VERSION 5.7 ;
  NOWIREEXTENSIONATPIN ON ;
  DIVIDERCHAR "/" ;
  BUSBITCHARS "[]" ;
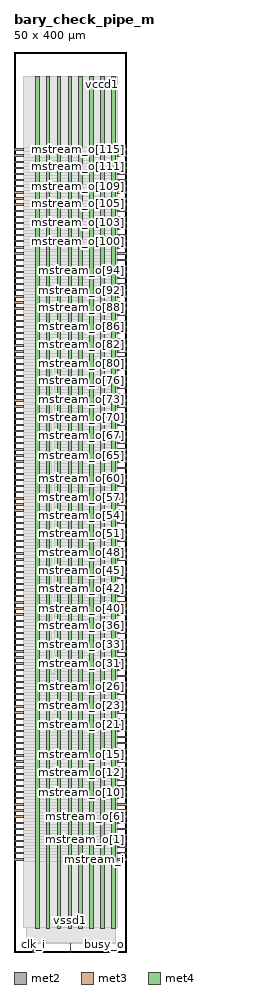
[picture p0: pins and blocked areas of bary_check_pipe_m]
MACRO bary_check_pipe_m
  CLASS BLOCK ;
  FOREIGN bary_check_pipe_m ;
  ORIGIN 0.000 0.000 ;
  SIZE 50.000 BY 400.000 ;
  PIN busy_o
    DIRECTION OUTPUT TRISTATE ;
    USE SIGNAL ;
    ANTENNADIFFAREA 0.891000 ;
    PORT
      LAYER met2 ;
        RECT 41.490 0.000 41.770 4.000 ;
    END
  END busy_o
  PIN clk_i
    DIRECTION INPUT ;
    USE SIGNAL ;
    ANTENNAGATEAREA 0.852000 ;
    PORT
      LAYER met2 ;
        RECT 8.370 0.000 8.650 4.000 ;
    END
  END clk_i
  PIN mstream_i
    DIRECTION INPUT ;
    USE SIGNAL ;
    ANTENNAGATEAREA 0.990000 ;
    PORT
      LAYER met3 ;
        RECT 46.000 40.840 50.000 41.440 ;
    END
  END mstream_i
  PIN mstream_o[0]
    DIRECTION OUTPUT TRISTATE ;
    USE SIGNAL ;
    ANTENNADIFFAREA 0.891000 ;
    PORT
      LAYER met3 ;
        RECT 46.000 43.560 50.000 44.160 ;
    END
  END mstream_o[0]
  PIN mstream_o[100]
    DIRECTION OUTPUT TRISTATE ;
    USE SIGNAL ;
    ANTENNADIFFAREA 0.891000 ;
    PORT
      LAYER met3 ;
        RECT 46.000 315.560 50.000 316.160 ;
    END
  END mstream_o[100]
  PIN mstream_o[101]
    DIRECTION OUTPUT TRISTATE ;
    USE SIGNAL ;
    ANTENNADIFFAREA 0.891000 ;
    PORT
      LAYER met3 ;
        RECT 46.000 318.280 50.000 318.880 ;
    END
  END mstream_o[101]
  PIN mstream_o[102]
    DIRECTION OUTPUT TRISTATE ;
    USE SIGNAL ;
    ANTENNADIFFAREA 0.891000 ;
    PORT
      LAYER met3 ;
        RECT 46.000 321.000 50.000 321.600 ;
    END
  END mstream_o[102]
  PIN mstream_o[103]
    DIRECTION OUTPUT TRISTATE ;
    USE SIGNAL ;
    ANTENNADIFFAREA 0.891000 ;
    PORT
      LAYER met3 ;
        RECT 46.000 323.720 50.000 324.320 ;
    END
  END mstream_o[103]
  PIN mstream_o[104]
    DIRECTION OUTPUT TRISTATE ;
    USE SIGNAL ;
    ANTENNADIFFAREA 0.891000 ;
    PORT
      LAYER met3 ;
        RECT 46.000 326.440 50.000 327.040 ;
    END
  END mstream_o[104]
  PIN mstream_o[105]
    DIRECTION OUTPUT TRISTATE ;
    USE SIGNAL ;
    ANTENNADIFFAREA 0.891000 ;
    PORT
      LAYER met3 ;
        RECT 46.000 329.160 50.000 329.760 ;
    END
  END mstream_o[105]
  PIN mstream_o[106]
    DIRECTION OUTPUT TRISTATE ;
    USE SIGNAL ;
    ANTENNADIFFAREA 0.891000 ;
    PORT
      LAYER met3 ;
        RECT 46.000 331.880 50.000 332.480 ;
    END
  END mstream_o[106]
  PIN mstream_o[107]
    DIRECTION OUTPUT TRISTATE ;
    USE SIGNAL ;
    ANTENNADIFFAREA 0.891000 ;
    PORT
      LAYER met3 ;
        RECT 46.000 334.600 50.000 335.200 ;
    END
  END mstream_o[107]
  PIN mstream_o[108]
    DIRECTION OUTPUT TRISTATE ;
    USE SIGNAL ;
    ANTENNADIFFAREA 0.891000 ;
    PORT
      LAYER met3 ;
        RECT 46.000 337.320 50.000 337.920 ;
    END
  END mstream_o[108]
  PIN mstream_o[109]
    DIRECTION OUTPUT TRISTATE ;
    USE SIGNAL ;
    ANTENNADIFFAREA 0.891000 ;
    PORT
      LAYER met3 ;
        RECT 46.000 340.040 50.000 340.640 ;
    END
  END mstream_o[109]
  PIN mstream_o[10]
    DIRECTION OUTPUT TRISTATE ;
    USE SIGNAL ;
    ANTENNADIFFAREA 0.891000 ;
    PORT
      LAYER met3 ;
        RECT 46.000 70.760 50.000 71.360 ;
    END
  END mstream_o[10]
  PIN mstream_o[110]
    DIRECTION OUTPUT TRISTATE ;
    USE SIGNAL ;
    ANTENNADIFFAREA 0.891000 ;
    PORT
      LAYER met3 ;
        RECT 46.000 342.760 50.000 343.360 ;
    END
  END mstream_o[110]
  PIN mstream_o[111]
    DIRECTION OUTPUT TRISTATE ;
    USE SIGNAL ;
    ANTENNADIFFAREA 0.891000 ;
    PORT
      LAYER met3 ;
        RECT 46.000 345.480 50.000 346.080 ;
    END
  END mstream_o[111]
  PIN mstream_o[112]
    DIRECTION OUTPUT TRISTATE ;
    USE SIGNAL ;
    ANTENNADIFFAREA 0.891000 ;
    PORT
      LAYER met3 ;
        RECT 46.000 348.200 50.000 348.800 ;
    END
  END mstream_o[112]
  PIN mstream_o[113]
    DIRECTION OUTPUT TRISTATE ;
    USE SIGNAL ;
    ANTENNADIFFAREA 0.891000 ;
    PORT
      LAYER met3 ;
        RECT 46.000 350.920 50.000 351.520 ;
    END
  END mstream_o[113]
  PIN mstream_o[114]
    DIRECTION OUTPUT TRISTATE ;
    USE SIGNAL ;
    ANTENNAGATEAREA 0.247500 ;
    ANTENNADIFFAREA 0.891000 ;
    PORT
      LAYER met3 ;
        RECT 46.000 353.640 50.000 354.240 ;
    END
  END mstream_o[114]
  PIN mstream_o[115]
    DIRECTION OUTPUT TRISTATE ;
    USE SIGNAL ;
    ANTENNADIFFAREA 0.891000 ;
    PORT
      LAYER met3 ;
        RECT 46.000 356.360 50.000 356.960 ;
    END
  END mstream_o[115]
  PIN mstream_o[11]
    DIRECTION OUTPUT TRISTATE ;
    USE SIGNAL ;
    ANTENNADIFFAREA 0.891000 ;
    PORT
      LAYER met3 ;
        RECT 46.000 73.480 50.000 74.080 ;
    END
  END mstream_o[11]
  PIN mstream_o[12]
    DIRECTION OUTPUT TRISTATE ;
    USE SIGNAL ;
    ANTENNADIFFAREA 0.891000 ;
    PORT
      LAYER met3 ;
        RECT 46.000 76.200 50.000 76.800 ;
    END
  END mstream_o[12]
  PIN mstream_o[13]
    DIRECTION OUTPUT TRISTATE ;
    USE SIGNAL ;
    ANTENNADIFFAREA 0.891000 ;
    PORT
      LAYER met3 ;
        RECT 46.000 78.920 50.000 79.520 ;
    END
  END mstream_o[13]
  PIN mstream_o[14]
    DIRECTION OUTPUT TRISTATE ;
    USE SIGNAL ;
    ANTENNADIFFAREA 0.891000 ;
    PORT
      LAYER met3 ;
        RECT 46.000 81.640 50.000 82.240 ;
    END
  END mstream_o[14]
  PIN mstream_o[15]
    DIRECTION OUTPUT TRISTATE ;
    USE SIGNAL ;
    ANTENNADIFFAREA 0.891000 ;
    PORT
      LAYER met3 ;
        RECT 46.000 84.360 50.000 84.960 ;
    END
  END mstream_o[15]
  PIN mstream_o[16]
    DIRECTION OUTPUT TRISTATE ;
    USE SIGNAL ;
    ANTENNADIFFAREA 0.891000 ;
    PORT
      LAYER met3 ;
        RECT 46.000 87.080 50.000 87.680 ;
    END
  END mstream_o[16]
  PIN mstream_o[17]
    DIRECTION OUTPUT TRISTATE ;
    USE SIGNAL ;
    ANTENNADIFFAREA 0.891000 ;
    PORT
      LAYER met3 ;
        RECT 46.000 89.800 50.000 90.400 ;
    END
  END mstream_o[17]
  PIN mstream_o[18]
    DIRECTION OUTPUT TRISTATE ;
    USE SIGNAL ;
    ANTENNADIFFAREA 0.891000 ;
    PORT
      LAYER met3 ;
        RECT 46.000 92.520 50.000 93.120 ;
    END
  END mstream_o[18]
  PIN mstream_o[19]
    DIRECTION OUTPUT TRISTATE ;
    USE SIGNAL ;
    ANTENNADIFFAREA 0.891000 ;
    PORT
      LAYER met3 ;
        RECT 46.000 95.240 50.000 95.840 ;
    END
  END mstream_o[19]
  PIN mstream_o[1]
    DIRECTION OUTPUT TRISTATE ;
    USE SIGNAL ;
    ANTENNADIFFAREA 0.891000 ;
    PORT
      LAYER met3 ;
        RECT 46.000 46.280 50.000 46.880 ;
    END
  END mstream_o[1]
  PIN mstream_o[20]
    DIRECTION OUTPUT TRISTATE ;
    USE SIGNAL ;
    ANTENNADIFFAREA 0.891000 ;
    PORT
      LAYER met3 ;
        RECT 46.000 97.960 50.000 98.560 ;
    END
  END mstream_o[20]
  PIN mstream_o[21]
    DIRECTION OUTPUT TRISTATE ;
    USE SIGNAL ;
    ANTENNADIFFAREA 0.891000 ;
    PORT
      LAYER met3 ;
        RECT 46.000 100.680 50.000 101.280 ;
    END
  END mstream_o[21]
  PIN mstream_o[22]
    DIRECTION OUTPUT TRISTATE ;
    USE SIGNAL ;
    ANTENNADIFFAREA 0.891000 ;
    PORT
      LAYER met3 ;
        RECT 46.000 103.400 50.000 104.000 ;
    END
  END mstream_o[22]
  PIN mstream_o[23]
    DIRECTION OUTPUT TRISTATE ;
    USE SIGNAL ;
    ANTENNADIFFAREA 0.891000 ;
    PORT
      LAYER met3 ;
        RECT 46.000 106.120 50.000 106.720 ;
    END
  END mstream_o[23]
  PIN mstream_o[24]
    DIRECTION OUTPUT TRISTATE ;
    USE SIGNAL ;
    ANTENNADIFFAREA 0.891000 ;
    PORT
      LAYER met3 ;
        RECT 46.000 108.840 50.000 109.440 ;
    END
  END mstream_o[24]
  PIN mstream_o[25]
    DIRECTION OUTPUT TRISTATE ;
    USE SIGNAL ;
    ANTENNADIFFAREA 0.891000 ;
    PORT
      LAYER met3 ;
        RECT 46.000 111.560 50.000 112.160 ;
    END
  END mstream_o[25]
  PIN mstream_o[26]
    DIRECTION OUTPUT TRISTATE ;
    USE SIGNAL ;
    ANTENNADIFFAREA 0.891000 ;
    PORT
      LAYER met3 ;
        RECT 46.000 114.280 50.000 114.880 ;
    END
  END mstream_o[26]
  PIN mstream_o[27]
    DIRECTION OUTPUT TRISTATE ;
    USE SIGNAL ;
    ANTENNADIFFAREA 0.891000 ;
    PORT
      LAYER met3 ;
        RECT 46.000 117.000 50.000 117.600 ;
    END
  END mstream_o[27]
  PIN mstream_o[28]
    DIRECTION OUTPUT TRISTATE ;
    USE SIGNAL ;
    ANTENNADIFFAREA 0.891000 ;
    PORT
      LAYER met3 ;
        RECT 46.000 119.720 50.000 120.320 ;
    END
  END mstream_o[28]
  PIN mstream_o[29]
    DIRECTION OUTPUT TRISTATE ;
    USE SIGNAL ;
    ANTENNADIFFAREA 0.891000 ;
    PORT
      LAYER met3 ;
        RECT 46.000 122.440 50.000 123.040 ;
    END
  END mstream_o[29]
  PIN mstream_o[2]
    DIRECTION OUTPUT TRISTATE ;
    USE SIGNAL ;
    ANTENNADIFFAREA 0.891000 ;
    PORT
      LAYER met3 ;
        RECT 46.000 49.000 50.000 49.600 ;
    END
  END mstream_o[2]
  PIN mstream_o[30]
    DIRECTION OUTPUT TRISTATE ;
    USE SIGNAL ;
    ANTENNADIFFAREA 0.891000 ;
    PORT
      LAYER met3 ;
        RECT 46.000 125.160 50.000 125.760 ;
    END
  END mstream_o[30]
  PIN mstream_o[31]
    DIRECTION OUTPUT TRISTATE ;
    USE SIGNAL ;
    ANTENNADIFFAREA 0.891000 ;
    PORT
      LAYER met3 ;
        RECT 46.000 127.880 50.000 128.480 ;
    END
  END mstream_o[31]
  PIN mstream_o[32]
    DIRECTION OUTPUT TRISTATE ;
    USE SIGNAL ;
    ANTENNADIFFAREA 0.891000 ;
    PORT
      LAYER met3 ;
        RECT 46.000 130.600 50.000 131.200 ;
    END
  END mstream_o[32]
  PIN mstream_o[33]
    DIRECTION OUTPUT TRISTATE ;
    USE SIGNAL ;
    ANTENNADIFFAREA 0.891000 ;
    PORT
      LAYER met3 ;
        RECT 46.000 133.320 50.000 133.920 ;
    END
  END mstream_o[33]
  PIN mstream_o[34]
    DIRECTION OUTPUT TRISTATE ;
    USE SIGNAL ;
    ANTENNADIFFAREA 0.891000 ;
    PORT
      LAYER met3 ;
        RECT 46.000 136.040 50.000 136.640 ;
    END
  END mstream_o[34]
  PIN mstream_o[35]
    DIRECTION OUTPUT TRISTATE ;
    USE SIGNAL ;
    ANTENNADIFFAREA 0.891000 ;
    PORT
      LAYER met3 ;
        RECT 46.000 138.760 50.000 139.360 ;
    END
  END mstream_o[35]
  PIN mstream_o[36]
    DIRECTION OUTPUT TRISTATE ;
    USE SIGNAL ;
    ANTENNADIFFAREA 0.891000 ;
    PORT
      LAYER met3 ;
        RECT 46.000 141.480 50.000 142.080 ;
    END
  END mstream_o[36]
  PIN mstream_o[37]
    DIRECTION OUTPUT TRISTATE ;
    USE SIGNAL ;
    ANTENNADIFFAREA 0.891000 ;
    PORT
      LAYER met3 ;
        RECT 46.000 144.200 50.000 144.800 ;
    END
  END mstream_o[37]
  PIN mstream_o[38]
    DIRECTION OUTPUT TRISTATE ;
    USE SIGNAL ;
    ANTENNADIFFAREA 0.891000 ;
    PORT
      LAYER met3 ;
        RECT 46.000 146.920 50.000 147.520 ;
    END
  END mstream_o[38]
  PIN mstream_o[39]
    DIRECTION OUTPUT TRISTATE ;
    USE SIGNAL ;
    ANTENNADIFFAREA 0.891000 ;
    PORT
      LAYER met3 ;
        RECT 46.000 149.640 50.000 150.240 ;
    END
  END mstream_o[39]
  PIN mstream_o[3]
    DIRECTION OUTPUT TRISTATE ;
    USE SIGNAL ;
    ANTENNADIFFAREA 0.891000 ;
    PORT
      LAYER met3 ;
        RECT 46.000 51.720 50.000 52.320 ;
    END
  END mstream_o[3]
  PIN mstream_o[40]
    DIRECTION OUTPUT TRISTATE ;
    USE SIGNAL ;
    ANTENNADIFFAREA 0.891000 ;
    PORT
      LAYER met3 ;
        RECT 46.000 152.360 50.000 152.960 ;
    END
  END mstream_o[40]
  PIN mstream_o[41]
    DIRECTION OUTPUT TRISTATE ;
    USE SIGNAL ;
    ANTENNADIFFAREA 0.891000 ;
    PORT
      LAYER met3 ;
        RECT 46.000 155.080 50.000 155.680 ;
    END
  END mstream_o[41]
  PIN mstream_o[42]
    DIRECTION OUTPUT TRISTATE ;
    USE SIGNAL ;
    ANTENNADIFFAREA 0.891000 ;
    PORT
      LAYER met3 ;
        RECT 46.000 157.800 50.000 158.400 ;
    END
  END mstream_o[42]
  PIN mstream_o[43]
    DIRECTION OUTPUT TRISTATE ;
    USE SIGNAL ;
    ANTENNADIFFAREA 0.891000 ;
    PORT
      LAYER met3 ;
        RECT 46.000 160.520 50.000 161.120 ;
    END
  END mstream_o[43]
  PIN mstream_o[44]
    DIRECTION OUTPUT TRISTATE ;
    USE SIGNAL ;
    ANTENNADIFFAREA 0.891000 ;
    PORT
      LAYER met3 ;
        RECT 46.000 163.240 50.000 163.840 ;
    END
  END mstream_o[44]
  PIN mstream_o[45]
    DIRECTION OUTPUT TRISTATE ;
    USE SIGNAL ;
    ANTENNADIFFAREA 0.891000 ;
    PORT
      LAYER met3 ;
        RECT 46.000 165.960 50.000 166.560 ;
    END
  END mstream_o[45]
  PIN mstream_o[46]
    DIRECTION OUTPUT TRISTATE ;
    USE SIGNAL ;
    ANTENNADIFFAREA 0.891000 ;
    PORT
      LAYER met3 ;
        RECT 46.000 168.680 50.000 169.280 ;
    END
  END mstream_o[46]
  PIN mstream_o[47]
    DIRECTION OUTPUT TRISTATE ;
    USE SIGNAL ;
    ANTENNADIFFAREA 0.891000 ;
    PORT
      LAYER met3 ;
        RECT 46.000 171.400 50.000 172.000 ;
    END
  END mstream_o[47]
  PIN mstream_o[48]
    DIRECTION OUTPUT TRISTATE ;
    USE SIGNAL ;
    ANTENNADIFFAREA 0.891000 ;
    PORT
      LAYER met3 ;
        RECT 46.000 174.120 50.000 174.720 ;
    END
  END mstream_o[48]
  PIN mstream_o[49]
    DIRECTION OUTPUT TRISTATE ;
    USE SIGNAL ;
    ANTENNADIFFAREA 0.891000 ;
    PORT
      LAYER met3 ;
        RECT 46.000 176.840 50.000 177.440 ;
    END
  END mstream_o[49]
  PIN mstream_o[4]
    DIRECTION OUTPUT TRISTATE ;
    USE SIGNAL ;
    ANTENNADIFFAREA 0.891000 ;
    PORT
      LAYER met3 ;
        RECT 46.000 54.440 50.000 55.040 ;
    END
  END mstream_o[4]
  PIN mstream_o[50]
    DIRECTION OUTPUT TRISTATE ;
    USE SIGNAL ;
    ANTENNADIFFAREA 0.891000 ;
    PORT
      LAYER met3 ;
        RECT 46.000 179.560 50.000 180.160 ;
    END
  END mstream_o[50]
  PIN mstream_o[51]
    DIRECTION OUTPUT TRISTATE ;
    USE SIGNAL ;
    ANTENNADIFFAREA 0.891000 ;
    PORT
      LAYER met3 ;
        RECT 46.000 182.280 50.000 182.880 ;
    END
  END mstream_o[51]
  PIN mstream_o[52]
    DIRECTION OUTPUT TRISTATE ;
    USE SIGNAL ;
    ANTENNADIFFAREA 0.891000 ;
    PORT
      LAYER met3 ;
        RECT 46.000 185.000 50.000 185.600 ;
    END
  END mstream_o[52]
  PIN mstream_o[53]
    DIRECTION OUTPUT TRISTATE ;
    USE SIGNAL ;
    ANTENNADIFFAREA 0.891000 ;
    PORT
      LAYER met3 ;
        RECT 46.000 187.720 50.000 188.320 ;
    END
  END mstream_o[53]
  PIN mstream_o[54]
    DIRECTION OUTPUT TRISTATE ;
    USE SIGNAL ;
    ANTENNADIFFAREA 0.891000 ;
    PORT
      LAYER met3 ;
        RECT 46.000 190.440 50.000 191.040 ;
    END
  END mstream_o[54]
  PIN mstream_o[55]
    DIRECTION OUTPUT TRISTATE ;
    USE SIGNAL ;
    ANTENNADIFFAREA 0.891000 ;
    PORT
      LAYER met3 ;
        RECT 46.000 193.160 50.000 193.760 ;
    END
  END mstream_o[55]
  PIN mstream_o[56]
    DIRECTION OUTPUT TRISTATE ;
    USE SIGNAL ;
    ANTENNADIFFAREA 0.891000 ;
    PORT
      LAYER met3 ;
        RECT 46.000 195.880 50.000 196.480 ;
    END
  END mstream_o[56]
  PIN mstream_o[57]
    DIRECTION OUTPUT TRISTATE ;
    USE SIGNAL ;
    ANTENNADIFFAREA 0.891000 ;
    PORT
      LAYER met3 ;
        RECT 46.000 198.600 50.000 199.200 ;
    END
  END mstream_o[57]
  PIN mstream_o[58]
    DIRECTION OUTPUT TRISTATE ;
    USE SIGNAL ;
    ANTENNADIFFAREA 0.891000 ;
    PORT
      LAYER met3 ;
        RECT 46.000 201.320 50.000 201.920 ;
    END
  END mstream_o[58]
  PIN mstream_o[59]
    DIRECTION OUTPUT TRISTATE ;
    USE SIGNAL ;
    ANTENNADIFFAREA 0.891000 ;
    PORT
      LAYER met3 ;
        RECT 46.000 204.040 50.000 204.640 ;
    END
  END mstream_o[59]
  PIN mstream_o[5]
    DIRECTION OUTPUT TRISTATE ;
    USE SIGNAL ;
    ANTENNADIFFAREA 0.891000 ;
    PORT
      LAYER met3 ;
        RECT 46.000 57.160 50.000 57.760 ;
    END
  END mstream_o[5]
  PIN mstream_o[60]
    DIRECTION OUTPUT TRISTATE ;
    USE SIGNAL ;
    ANTENNADIFFAREA 0.891000 ;
    PORT
      LAYER met3 ;
        RECT 46.000 206.760 50.000 207.360 ;
    END
  END mstream_o[60]
  PIN mstream_o[61]
    DIRECTION OUTPUT TRISTATE ;
    USE SIGNAL ;
    ANTENNADIFFAREA 0.891000 ;
    PORT
      LAYER met3 ;
        RECT 46.000 209.480 50.000 210.080 ;
    END
  END mstream_o[61]
  PIN mstream_o[62]
    DIRECTION OUTPUT TRISTATE ;
    USE SIGNAL ;
    ANTENNADIFFAREA 0.891000 ;
    PORT
      LAYER met3 ;
        RECT 46.000 212.200 50.000 212.800 ;
    END
  END mstream_o[62]
  PIN mstream_o[63]
    DIRECTION OUTPUT TRISTATE ;
    USE SIGNAL ;
    ANTENNADIFFAREA 0.891000 ;
    PORT
      LAYER met3 ;
        RECT 46.000 214.920 50.000 215.520 ;
    END
  END mstream_o[63]
  PIN mstream_o[64]
    DIRECTION OUTPUT TRISTATE ;
    USE SIGNAL ;
    ANTENNADIFFAREA 0.891000 ;
    PORT
      LAYER met3 ;
        RECT 46.000 217.640 50.000 218.240 ;
    END
  END mstream_o[64]
  PIN mstream_o[65]
    DIRECTION OUTPUT TRISTATE ;
    USE SIGNAL ;
    ANTENNADIFFAREA 0.891000 ;
    PORT
      LAYER met3 ;
        RECT 46.000 220.360 50.000 220.960 ;
    END
  END mstream_o[65]
  PIN mstream_o[66]
    DIRECTION OUTPUT TRISTATE ;
    USE SIGNAL ;
    ANTENNADIFFAREA 0.891000 ;
    PORT
      LAYER met3 ;
        RECT 46.000 223.080 50.000 223.680 ;
    END
  END mstream_o[66]
  PIN mstream_o[67]
    DIRECTION OUTPUT TRISTATE ;
    USE SIGNAL ;
    ANTENNADIFFAREA 0.891000 ;
    PORT
      LAYER met3 ;
        RECT 46.000 225.800 50.000 226.400 ;
    END
  END mstream_o[67]
  PIN mstream_o[68]
    DIRECTION OUTPUT TRISTATE ;
    USE SIGNAL ;
    ANTENNADIFFAREA 0.891000 ;
    PORT
      LAYER met3 ;
        RECT 46.000 228.520 50.000 229.120 ;
    END
  END mstream_o[68]
  PIN mstream_o[69]
    DIRECTION OUTPUT TRISTATE ;
    USE SIGNAL ;
    ANTENNADIFFAREA 0.891000 ;
    PORT
      LAYER met3 ;
        RECT 46.000 231.240 50.000 231.840 ;
    END
  END mstream_o[69]
  PIN mstream_o[6]
    DIRECTION OUTPUT TRISTATE ;
    USE SIGNAL ;
    ANTENNADIFFAREA 0.891000 ;
    PORT
      LAYER met3 ;
        RECT 46.000 59.880 50.000 60.480 ;
    END
  END mstream_o[6]
  PIN mstream_o[70]
    DIRECTION OUTPUT TRISTATE ;
    USE SIGNAL ;
    ANTENNADIFFAREA 0.891000 ;
    PORT
      LAYER met3 ;
        RECT 46.000 233.960 50.000 234.560 ;
    END
  END mstream_o[70]
  PIN mstream_o[71]
    DIRECTION OUTPUT TRISTATE ;
    USE SIGNAL ;
    ANTENNADIFFAREA 0.891000 ;
    PORT
      LAYER met3 ;
        RECT 46.000 236.680 50.000 237.280 ;
    END
  END mstream_o[71]
  PIN mstream_o[72]
    DIRECTION OUTPUT TRISTATE ;
    USE SIGNAL ;
    ANTENNADIFFAREA 0.891000 ;
    PORT
      LAYER met3 ;
        RECT 46.000 239.400 50.000 240.000 ;
    END
  END mstream_o[72]
  PIN mstream_o[73]
    DIRECTION OUTPUT TRISTATE ;
    USE SIGNAL ;
    ANTENNADIFFAREA 0.891000 ;
    PORT
      LAYER met3 ;
        RECT 46.000 242.120 50.000 242.720 ;
    END
  END mstream_o[73]
  PIN mstream_o[74]
    DIRECTION OUTPUT TRISTATE ;
    USE SIGNAL ;
    ANTENNADIFFAREA 0.891000 ;
    PORT
      LAYER met3 ;
        RECT 46.000 244.840 50.000 245.440 ;
    END
  END mstream_o[74]
  PIN mstream_o[75]
    DIRECTION OUTPUT TRISTATE ;
    USE SIGNAL ;
    ANTENNADIFFAREA 0.891000 ;
    PORT
      LAYER met3 ;
        RECT 46.000 247.560 50.000 248.160 ;
    END
  END mstream_o[75]
  PIN mstream_o[76]
    DIRECTION OUTPUT TRISTATE ;
    USE SIGNAL ;
    ANTENNADIFFAREA 0.891000 ;
    PORT
      LAYER met3 ;
        RECT 46.000 250.280 50.000 250.880 ;
    END
  END mstream_o[76]
  PIN mstream_o[77]
    DIRECTION OUTPUT TRISTATE ;
    USE SIGNAL ;
    ANTENNADIFFAREA 0.891000 ;
    PORT
      LAYER met3 ;
        RECT 46.000 253.000 50.000 253.600 ;
    END
  END mstream_o[77]
  PIN mstream_o[78]
    DIRECTION OUTPUT TRISTATE ;
    USE SIGNAL ;
    ANTENNADIFFAREA 0.891000 ;
    PORT
      LAYER met3 ;
        RECT 46.000 255.720 50.000 256.320 ;
    END
  END mstream_o[78]
  PIN mstream_o[79]
    DIRECTION OUTPUT TRISTATE ;
    USE SIGNAL ;
    ANTENNADIFFAREA 0.891000 ;
    PORT
      LAYER met3 ;
        RECT 46.000 258.440 50.000 259.040 ;
    END
  END mstream_o[79]
  PIN mstream_o[7]
    DIRECTION OUTPUT TRISTATE ;
    USE SIGNAL ;
    ANTENNADIFFAREA 0.891000 ;
    PORT
      LAYER met3 ;
        RECT 46.000 62.600 50.000 63.200 ;
    END
  END mstream_o[7]
  PIN mstream_o[80]
    DIRECTION OUTPUT TRISTATE ;
    USE SIGNAL ;
    ANTENNADIFFAREA 0.891000 ;
    PORT
      LAYER met3 ;
        RECT 46.000 261.160 50.000 261.760 ;
    END
  END mstream_o[80]
  PIN mstream_o[81]
    DIRECTION OUTPUT TRISTATE ;
    USE SIGNAL ;
    ANTENNADIFFAREA 0.891000 ;
    PORT
      LAYER met3 ;
        RECT 46.000 263.880 50.000 264.480 ;
    END
  END mstream_o[81]
  PIN mstream_o[82]
    DIRECTION OUTPUT TRISTATE ;
    USE SIGNAL ;
    ANTENNADIFFAREA 0.891000 ;
    PORT
      LAYER met3 ;
        RECT 46.000 266.600 50.000 267.200 ;
    END
  END mstream_o[82]
  PIN mstream_o[83]
    DIRECTION OUTPUT TRISTATE ;
    USE SIGNAL ;
    ANTENNADIFFAREA 0.891000 ;
    PORT
      LAYER met3 ;
        RECT 46.000 269.320 50.000 269.920 ;
    END
  END mstream_o[83]
  PIN mstream_o[84]
    DIRECTION OUTPUT TRISTATE ;
    USE SIGNAL ;
    ANTENNADIFFAREA 0.891000 ;
    PORT
      LAYER met3 ;
        RECT 46.000 272.040 50.000 272.640 ;
    END
  END mstream_o[84]
  PIN mstream_o[85]
    DIRECTION OUTPUT TRISTATE ;
    USE SIGNAL ;
    ANTENNADIFFAREA 0.891000 ;
    PORT
      LAYER met3 ;
        RECT 46.000 274.760 50.000 275.360 ;
    END
  END mstream_o[85]
  PIN mstream_o[86]
    DIRECTION OUTPUT TRISTATE ;
    USE SIGNAL ;
    ANTENNADIFFAREA 0.891000 ;
    PORT
      LAYER met3 ;
        RECT 46.000 277.480 50.000 278.080 ;
    END
  END mstream_o[86]
  PIN mstream_o[87]
    DIRECTION OUTPUT TRISTATE ;
    USE SIGNAL ;
    ANTENNADIFFAREA 0.891000 ;
    PORT
      LAYER met3 ;
        RECT 46.000 280.200 50.000 280.800 ;
    END
  END mstream_o[87]
  PIN mstream_o[88]
    DIRECTION OUTPUT TRISTATE ;
    USE SIGNAL ;
    ANTENNADIFFAREA 0.891000 ;
    PORT
      LAYER met3 ;
        RECT 46.000 282.920 50.000 283.520 ;
    END
  END mstream_o[88]
  PIN mstream_o[89]
    DIRECTION OUTPUT TRISTATE ;
    USE SIGNAL ;
    ANTENNADIFFAREA 0.891000 ;
    PORT
      LAYER met3 ;
        RECT 46.000 285.640 50.000 286.240 ;
    END
  END mstream_o[89]
  PIN mstream_o[8]
    DIRECTION OUTPUT TRISTATE ;
    USE SIGNAL ;
    ANTENNADIFFAREA 0.891000 ;
    PORT
      LAYER met3 ;
        RECT 46.000 65.320 50.000 65.920 ;
    END
  END mstream_o[8]
  PIN mstream_o[90]
    DIRECTION OUTPUT TRISTATE ;
    USE SIGNAL ;
    ANTENNADIFFAREA 0.891000 ;
    PORT
      LAYER met3 ;
        RECT 46.000 288.360 50.000 288.960 ;
    END
  END mstream_o[90]
  PIN mstream_o[91]
    DIRECTION OUTPUT TRISTATE ;
    USE SIGNAL ;
    ANTENNADIFFAREA 0.891000 ;
    PORT
      LAYER met3 ;
        RECT 46.000 291.080 50.000 291.680 ;
    END
  END mstream_o[91]
  PIN mstream_o[92]
    DIRECTION OUTPUT TRISTATE ;
    USE SIGNAL ;
    ANTENNADIFFAREA 0.891000 ;
    PORT
      LAYER met3 ;
        RECT 46.000 293.800 50.000 294.400 ;
    END
  END mstream_o[92]
  PIN mstream_o[93]
    DIRECTION OUTPUT TRISTATE ;
    USE SIGNAL ;
    ANTENNADIFFAREA 0.891000 ;
    PORT
      LAYER met3 ;
        RECT 46.000 296.520 50.000 297.120 ;
    END
  END mstream_o[93]
  PIN mstream_o[94]
    DIRECTION OUTPUT TRISTATE ;
    USE SIGNAL ;
    ANTENNADIFFAREA 0.891000 ;
    PORT
      LAYER met3 ;
        RECT 46.000 299.240 50.000 299.840 ;
    END
  END mstream_o[94]
  PIN mstream_o[95]
    DIRECTION OUTPUT TRISTATE ;
    USE SIGNAL ;
    ANTENNADIFFAREA 0.891000 ;
    PORT
      LAYER met3 ;
        RECT 46.000 301.960 50.000 302.560 ;
    END
  END mstream_o[95]
  PIN mstream_o[96]
    DIRECTION OUTPUT TRISTATE ;
    USE SIGNAL ;
    ANTENNADIFFAREA 0.891000 ;
    PORT
      LAYER met3 ;
        RECT 46.000 304.680 50.000 305.280 ;
    END
  END mstream_o[96]
  PIN mstream_o[97]
    DIRECTION OUTPUT TRISTATE ;
    USE SIGNAL ;
    ANTENNADIFFAREA 0.891000 ;
    PORT
      LAYER met3 ;
        RECT 46.000 307.400 50.000 308.000 ;
    END
  END mstream_o[97]
  PIN mstream_o[98]
    DIRECTION OUTPUT TRISTATE ;
    USE SIGNAL ;
    ANTENNADIFFAREA 0.891000 ;
    PORT
      LAYER met3 ;
        RECT 46.000 310.120 50.000 310.720 ;
    END
  END mstream_o[98]
  PIN mstream_o[99]
    DIRECTION OUTPUT TRISTATE ;
    USE SIGNAL ;
    ANTENNADIFFAREA 0.891000 ;
    PORT
      LAYER met3 ;
        RECT 46.000 312.840 50.000 313.440 ;
    END
  END mstream_o[99]
  PIN mstream_o[9]
    DIRECTION OUTPUT TRISTATE ;
    USE SIGNAL ;
    ANTENNADIFFAREA 0.891000 ;
    PORT
      LAYER met3 ;
        RECT 46.000 68.040 50.000 68.640 ;
    END
  END mstream_o[9]
  PIN nrst_i
    DIRECTION INPUT ;
    USE SIGNAL ;
    ANTENNAGATEAREA 0.247500 ;
    PORT
      LAYER met2 ;
        RECT 24.930 0.000 25.210 4.000 ;
    END
  END nrst_i
  PIN sstream_i[0]
    DIRECTION INPUT ;
    USE SIGNAL ;
    ANTENNAGATEAREA 0.126000 ;
    PORT
      LAYER met3 ;
        RECT 0.000 40.840 4.000 41.440 ;
    END
  END sstream_i[0]
  PIN sstream_i[100]
    DIRECTION INPUT ;
    USE SIGNAL ;
    ANTENNAGATEAREA 0.126000 ;
    PORT
      LAYER met3 ;
        RECT 0.000 312.840 4.000 313.440 ;
    END
  END sstream_i[100]
  PIN sstream_i[101]
    DIRECTION INPUT ;
    USE SIGNAL ;
    ANTENNAGATEAREA 0.126000 ;
    PORT
      LAYER met3 ;
        RECT 0.000 315.560 4.000 316.160 ;
    END
  END sstream_i[101]
  PIN sstream_i[102]
    DIRECTION INPUT ;
    USE SIGNAL ;
    ANTENNAGATEAREA 0.126000 ;
    PORT
      LAYER met3 ;
        RECT 0.000 318.280 4.000 318.880 ;
    END
  END sstream_i[102]
  PIN sstream_i[103]
    DIRECTION INPUT ;
    USE SIGNAL ;
    ANTENNAGATEAREA 0.126000 ;
    PORT
      LAYER met3 ;
        RECT 0.000 321.000 4.000 321.600 ;
    END
  END sstream_i[103]
  PIN sstream_i[104]
    DIRECTION INPUT ;
    USE SIGNAL ;
    ANTENNAGATEAREA 0.126000 ;
    PORT
      LAYER met3 ;
        RECT 0.000 323.720 4.000 324.320 ;
    END
  END sstream_i[104]
  PIN sstream_i[105]
    DIRECTION INPUT ;
    USE SIGNAL ;
    ANTENNAGATEAREA 0.126000 ;
    PORT
      LAYER met3 ;
        RECT 0.000 326.440 4.000 327.040 ;
    END
  END sstream_i[105]
  PIN sstream_i[106]
    DIRECTION INPUT ;
    USE SIGNAL ;
    ANTENNAGATEAREA 0.126000 ;
    PORT
      LAYER met3 ;
        RECT 0.000 329.160 4.000 329.760 ;
    END
  END sstream_i[106]
  PIN sstream_i[107]
    DIRECTION INPUT ;
    USE SIGNAL ;
    ANTENNAGATEAREA 0.126000 ;
    PORT
      LAYER met3 ;
        RECT 0.000 331.880 4.000 332.480 ;
    END
  END sstream_i[107]
  PIN sstream_i[108]
    DIRECTION INPUT ;
    USE SIGNAL ;
    ANTENNAGATEAREA 0.126000 ;
    PORT
      LAYER met3 ;
        RECT 0.000 334.600 4.000 335.200 ;
    END
  END sstream_i[108]
  PIN sstream_i[109]
    DIRECTION INPUT ;
    USE SIGNAL ;
    ANTENNAGATEAREA 0.126000 ;
    PORT
      LAYER met3 ;
        RECT 0.000 337.320 4.000 337.920 ;
    END
  END sstream_i[109]
  PIN sstream_i[10]
    DIRECTION INPUT ;
    USE SIGNAL ;
    ANTENNAGATEAREA 0.126000 ;
    PORT
      LAYER met3 ;
        RECT 0.000 68.040 4.000 68.640 ;
    END
  END sstream_i[10]
  PIN sstream_i[110]
    DIRECTION INPUT ;
    USE SIGNAL ;
    ANTENNAGATEAREA 0.126000 ;
    PORT
      LAYER met3 ;
        RECT 0.000 340.040 4.000 340.640 ;
    END
  END sstream_i[110]
  PIN sstream_i[111]
    DIRECTION INPUT ;
    USE SIGNAL ;
    ANTENNAGATEAREA 0.126000 ;
    PORT
      LAYER met3 ;
        RECT 0.000 342.760 4.000 343.360 ;
    END
  END sstream_i[111]
  PIN sstream_i[112]
    DIRECTION INPUT ;
    USE SIGNAL ;
    ANTENNAGATEAREA 0.126000 ;
    PORT
      LAYER met3 ;
        RECT 0.000 345.480 4.000 346.080 ;
    END
  END sstream_i[112]
  PIN sstream_i[113]
    DIRECTION INPUT ;
    USE SIGNAL ;
    ANTENNAGATEAREA 0.126000 ;
    PORT
      LAYER met3 ;
        RECT 0.000 348.200 4.000 348.800 ;
    END
  END sstream_i[113]
  PIN sstream_i[114]
    DIRECTION INPUT ;
    USE SIGNAL ;
    ANTENNAGATEAREA 0.373500 ;
    PORT
      LAYER met3 ;
        RECT 0.000 350.920 4.000 351.520 ;
    END
  END sstream_i[114]
  PIN sstream_i[115]
    DIRECTION INPUT ;
    USE SIGNAL ;
    ANTENNAGATEAREA 0.126000 ;
    PORT
      LAYER met3 ;
        RECT 0.000 353.640 4.000 354.240 ;
    END
  END sstream_i[115]
  PIN sstream_i[11]
    DIRECTION INPUT ;
    USE SIGNAL ;
    ANTENNAGATEAREA 0.126000 ;
    PORT
      LAYER met3 ;
        RECT 0.000 70.760 4.000 71.360 ;
    END
  END sstream_i[11]
  PIN sstream_i[12]
    DIRECTION INPUT ;
    USE SIGNAL ;
    ANTENNAGATEAREA 0.126000 ;
    PORT
      LAYER met3 ;
        RECT 0.000 73.480 4.000 74.080 ;
    END
  END sstream_i[12]
  PIN sstream_i[13]
    DIRECTION INPUT ;
    USE SIGNAL ;
    ANTENNAGATEAREA 0.126000 ;
    PORT
      LAYER met3 ;
        RECT 0.000 76.200 4.000 76.800 ;
    END
  END sstream_i[13]
  PIN sstream_i[14]
    DIRECTION INPUT ;
    USE SIGNAL ;
    ANTENNAGATEAREA 0.126000 ;
    PORT
      LAYER met3 ;
        RECT 0.000 78.920 4.000 79.520 ;
    END
  END sstream_i[14]
  PIN sstream_i[15]
    DIRECTION INPUT ;
    USE SIGNAL ;
    ANTENNAGATEAREA 0.126000 ;
    PORT
      LAYER met3 ;
        RECT 0.000 81.640 4.000 82.240 ;
    END
  END sstream_i[15]
  PIN sstream_i[16]
    DIRECTION INPUT ;
    USE SIGNAL ;
    ANTENNAGATEAREA 0.126000 ;
    PORT
      LAYER met3 ;
        RECT 0.000 84.360 4.000 84.960 ;
    END
  END sstream_i[16]
  PIN sstream_i[17]
    DIRECTION INPUT ;
    USE SIGNAL ;
    ANTENNAGATEAREA 0.126000 ;
    PORT
      LAYER met3 ;
        RECT 0.000 87.080 4.000 87.680 ;
    END
  END sstream_i[17]
  PIN sstream_i[18]
    DIRECTION INPUT ;
    USE SIGNAL ;
    ANTENNAGATEAREA 0.126000 ;
    PORT
      LAYER met3 ;
        RECT 0.000 89.800 4.000 90.400 ;
    END
  END sstream_i[18]
  PIN sstream_i[19]
    DIRECTION INPUT ;
    USE SIGNAL ;
    ANTENNAGATEAREA 0.126000 ;
    PORT
      LAYER met3 ;
        RECT 0.000 92.520 4.000 93.120 ;
    END
  END sstream_i[19]
  PIN sstream_i[1]
    DIRECTION INPUT ;
    USE SIGNAL ;
    ANTENNAGATEAREA 0.126000 ;
    PORT
      LAYER met3 ;
        RECT 0.000 43.560 4.000 44.160 ;
    END
  END sstream_i[1]
  PIN sstream_i[20]
    DIRECTION INPUT ;
    USE SIGNAL ;
    ANTENNAGATEAREA 0.126000 ;
    PORT
      LAYER met3 ;
        RECT 0.000 95.240 4.000 95.840 ;
    END
  END sstream_i[20]
  PIN sstream_i[21]
    DIRECTION INPUT ;
    USE SIGNAL ;
    ANTENNAGATEAREA 0.126000 ;
    PORT
      LAYER met3 ;
        RECT 0.000 97.960 4.000 98.560 ;
    END
  END sstream_i[21]
  PIN sstream_i[22]
    DIRECTION INPUT ;
    USE SIGNAL ;
    ANTENNAGATEAREA 0.126000 ;
    PORT
      LAYER met3 ;
        RECT 0.000 100.680 4.000 101.280 ;
    END
  END sstream_i[22]
  PIN sstream_i[23]
    DIRECTION INPUT ;
    USE SIGNAL ;
    ANTENNAGATEAREA 0.126000 ;
    PORT
      LAYER met3 ;
        RECT 0.000 103.400 4.000 104.000 ;
    END
  END sstream_i[23]
  PIN sstream_i[24]
    DIRECTION INPUT ;
    USE SIGNAL ;
    ANTENNAGATEAREA 0.126000 ;
    PORT
      LAYER met3 ;
        RECT 0.000 106.120 4.000 106.720 ;
    END
  END sstream_i[24]
  PIN sstream_i[25]
    DIRECTION INPUT ;
    USE SIGNAL ;
    ANTENNAGATEAREA 0.126000 ;
    PORT
      LAYER met3 ;
        RECT 0.000 108.840 4.000 109.440 ;
    END
  END sstream_i[25]
  PIN sstream_i[26]
    DIRECTION INPUT ;
    USE SIGNAL ;
    ANTENNAGATEAREA 0.126000 ;
    PORT
      LAYER met3 ;
        RECT 0.000 111.560 4.000 112.160 ;
    END
  END sstream_i[26]
  PIN sstream_i[27]
    DIRECTION INPUT ;
    USE SIGNAL ;
    ANTENNAGATEAREA 0.126000 ;
    PORT
      LAYER met3 ;
        RECT 0.000 114.280 4.000 114.880 ;
    END
  END sstream_i[27]
  PIN sstream_i[28]
    DIRECTION INPUT ;
    USE SIGNAL ;
    ANTENNAGATEAREA 0.126000 ;
    PORT
      LAYER met3 ;
        RECT 0.000 117.000 4.000 117.600 ;
    END
  END sstream_i[28]
  PIN sstream_i[29]
    DIRECTION INPUT ;
    USE SIGNAL ;
    ANTENNAGATEAREA 0.126000 ;
    PORT
      LAYER met3 ;
        RECT 0.000 119.720 4.000 120.320 ;
    END
  END sstream_i[29]
  PIN sstream_i[2]
    DIRECTION INPUT ;
    USE SIGNAL ;
    ANTENNAGATEAREA 0.126000 ;
    PORT
      LAYER met3 ;
        RECT 0.000 46.280 4.000 46.880 ;
    END
  END sstream_i[2]
  PIN sstream_i[30]
    DIRECTION INPUT ;
    USE SIGNAL ;
    ANTENNAGATEAREA 0.126000 ;
    PORT
      LAYER met3 ;
        RECT 0.000 122.440 4.000 123.040 ;
    END
  END sstream_i[30]
  PIN sstream_i[31]
    DIRECTION INPUT ;
    USE SIGNAL ;
    ANTENNAGATEAREA 0.213000 ;
    PORT
      LAYER met3 ;
        RECT 0.000 125.160 4.000 125.760 ;
    END
  END sstream_i[31]
  PIN sstream_i[32]
    DIRECTION INPUT ;
    USE SIGNAL ;
    ANTENNAGATEAREA 0.126000 ;
    PORT
      LAYER met3 ;
        RECT 0.000 127.880 4.000 128.480 ;
    END
  END sstream_i[32]
  PIN sstream_i[33]
    DIRECTION INPUT ;
    USE SIGNAL ;
    ANTENNAGATEAREA 0.126000 ;
    PORT
      LAYER met3 ;
        RECT 0.000 130.600 4.000 131.200 ;
    END
  END sstream_i[33]
  PIN sstream_i[34]
    DIRECTION INPUT ;
    USE SIGNAL ;
    ANTENNAGATEAREA 0.126000 ;
    PORT
      LAYER met3 ;
        RECT 0.000 133.320 4.000 133.920 ;
    END
  END sstream_i[34]
  PIN sstream_i[35]
    DIRECTION INPUT ;
    USE SIGNAL ;
    ANTENNAGATEAREA 0.126000 ;
    PORT
      LAYER met3 ;
        RECT 0.000 136.040 4.000 136.640 ;
    END
  END sstream_i[35]
  PIN sstream_i[36]
    DIRECTION INPUT ;
    USE SIGNAL ;
    ANTENNAGATEAREA 0.126000 ;
    PORT
      LAYER met3 ;
        RECT 0.000 138.760 4.000 139.360 ;
    END
  END sstream_i[36]
  PIN sstream_i[37]
    DIRECTION INPUT ;
    USE SIGNAL ;
    ANTENNAGATEAREA 0.126000 ;
    PORT
      LAYER met3 ;
        RECT 0.000 141.480 4.000 142.080 ;
    END
  END sstream_i[37]
  PIN sstream_i[38]
    DIRECTION INPUT ;
    USE SIGNAL ;
    ANTENNAGATEAREA 0.126000 ;
    PORT
      LAYER met3 ;
        RECT 0.000 144.200 4.000 144.800 ;
    END
  END sstream_i[38]
  PIN sstream_i[39]
    DIRECTION INPUT ;
    USE SIGNAL ;
    ANTENNAGATEAREA 0.126000 ;
    PORT
      LAYER met3 ;
        RECT 0.000 146.920 4.000 147.520 ;
    END
  END sstream_i[39]
  PIN sstream_i[3]
    DIRECTION INPUT ;
    USE SIGNAL ;
    ANTENNAGATEAREA 0.126000 ;
    PORT
      LAYER met3 ;
        RECT 0.000 49.000 4.000 49.600 ;
    END
  END sstream_i[3]
  PIN sstream_i[40]
    DIRECTION INPUT ;
    USE SIGNAL ;
    ANTENNAGATEAREA 0.126000 ;
    PORT
      LAYER met3 ;
        RECT 0.000 149.640 4.000 150.240 ;
    END
  END sstream_i[40]
  PIN sstream_i[41]
    DIRECTION INPUT ;
    USE SIGNAL ;
    ANTENNAGATEAREA 0.126000 ;
    PORT
      LAYER met3 ;
        RECT 0.000 152.360 4.000 152.960 ;
    END
  END sstream_i[41]
  PIN sstream_i[42]
    DIRECTION INPUT ;
    USE SIGNAL ;
    ANTENNAGATEAREA 0.126000 ;
    PORT
      LAYER met3 ;
        RECT 0.000 155.080 4.000 155.680 ;
    END
  END sstream_i[42]
  PIN sstream_i[43]
    DIRECTION INPUT ;
    USE SIGNAL ;
    ANTENNAGATEAREA 0.126000 ;
    PORT
      LAYER met3 ;
        RECT 0.000 157.800 4.000 158.400 ;
    END
  END sstream_i[43]
  PIN sstream_i[44]
    DIRECTION INPUT ;
    USE SIGNAL ;
    ANTENNAGATEAREA 0.126000 ;
    PORT
      LAYER met3 ;
        RECT 0.000 160.520 4.000 161.120 ;
    END
  END sstream_i[44]
  PIN sstream_i[45]
    DIRECTION INPUT ;
    USE SIGNAL ;
    ANTENNAGATEAREA 0.126000 ;
    PORT
      LAYER met3 ;
        RECT 0.000 163.240 4.000 163.840 ;
    END
  END sstream_i[45]
  PIN sstream_i[46]
    DIRECTION INPUT ;
    USE SIGNAL ;
    ANTENNAGATEAREA 0.126000 ;
    PORT
      LAYER met3 ;
        RECT 0.000 165.960 4.000 166.560 ;
    END
  END sstream_i[46]
  PIN sstream_i[47]
    DIRECTION INPUT ;
    USE SIGNAL ;
    ANTENNAGATEAREA 0.126000 ;
    PORT
      LAYER met3 ;
        RECT 0.000 168.680 4.000 169.280 ;
    END
  END sstream_i[47]
  PIN sstream_i[48]
    DIRECTION INPUT ;
    USE SIGNAL ;
    ANTENNAGATEAREA 0.126000 ;
    PORT
      LAYER met3 ;
        RECT 0.000 171.400 4.000 172.000 ;
    END
  END sstream_i[48]
  PIN sstream_i[49]
    DIRECTION INPUT ;
    USE SIGNAL ;
    ANTENNAGATEAREA 0.126000 ;
    PORT
      LAYER met3 ;
        RECT 0.000 174.120 4.000 174.720 ;
    END
  END sstream_i[49]
  PIN sstream_i[4]
    DIRECTION INPUT ;
    USE SIGNAL ;
    ANTENNAGATEAREA 0.126000 ;
    PORT
      LAYER met3 ;
        RECT 0.000 51.720 4.000 52.320 ;
    END
  END sstream_i[4]
  PIN sstream_i[50]
    DIRECTION INPUT ;
    USE SIGNAL ;
    ANTENNAGATEAREA 0.126000 ;
    PORT
      LAYER met3 ;
        RECT 0.000 176.840 4.000 177.440 ;
    END
  END sstream_i[50]
  PIN sstream_i[51]
    DIRECTION INPUT ;
    USE SIGNAL ;
    ANTENNAGATEAREA 0.126000 ;
    PORT
      LAYER met3 ;
        RECT 0.000 179.560 4.000 180.160 ;
    END
  END sstream_i[51]
  PIN sstream_i[52]
    DIRECTION INPUT ;
    USE SIGNAL ;
    ANTENNAGATEAREA 0.126000 ;
    PORT
      LAYER met3 ;
        RECT 0.000 182.280 4.000 182.880 ;
    END
  END sstream_i[52]
  PIN sstream_i[53]
    DIRECTION INPUT ;
    USE SIGNAL ;
    ANTENNAGATEAREA 0.126000 ;
    PORT
      LAYER met3 ;
        RECT 0.000 185.000 4.000 185.600 ;
    END
  END sstream_i[53]
  PIN sstream_i[54]
    DIRECTION INPUT ;
    USE SIGNAL ;
    ANTENNAGATEAREA 0.126000 ;
    PORT
      LAYER met3 ;
        RECT 0.000 187.720 4.000 188.320 ;
    END
  END sstream_i[54]
  PIN sstream_i[55]
    DIRECTION INPUT ;
    USE SIGNAL ;
    ANTENNAGATEAREA 0.126000 ;
    PORT
      LAYER met3 ;
        RECT 0.000 190.440 4.000 191.040 ;
    END
  END sstream_i[55]
  PIN sstream_i[56]
    DIRECTION INPUT ;
    USE SIGNAL ;
    ANTENNAGATEAREA 0.126000 ;
    PORT
      LAYER met3 ;
        RECT 0.000 193.160 4.000 193.760 ;
    END
  END sstream_i[56]
  PIN sstream_i[57]
    DIRECTION INPUT ;
    USE SIGNAL ;
    ANTENNAGATEAREA 0.126000 ;
    PORT
      LAYER met3 ;
        RECT 0.000 195.880 4.000 196.480 ;
    END
  END sstream_i[57]
  PIN sstream_i[58]
    DIRECTION INPUT ;
    USE SIGNAL ;
    ANTENNAGATEAREA 0.126000 ;
    PORT
      LAYER met3 ;
        RECT 0.000 198.600 4.000 199.200 ;
    END
  END sstream_i[58]
  PIN sstream_i[59]
    DIRECTION INPUT ;
    USE SIGNAL ;
    ANTENNAGATEAREA 0.126000 ;
    PORT
      LAYER met3 ;
        RECT 0.000 201.320 4.000 201.920 ;
    END
  END sstream_i[59]
  PIN sstream_i[5]
    DIRECTION INPUT ;
    USE SIGNAL ;
    ANTENNAGATEAREA 0.126000 ;
    PORT
      LAYER met3 ;
        RECT 0.000 54.440 4.000 55.040 ;
    END
  END sstream_i[5]
  PIN sstream_i[60]
    DIRECTION INPUT ;
    USE SIGNAL ;
    ANTENNAGATEAREA 0.126000 ;
    PORT
      LAYER met3 ;
        RECT 0.000 204.040 4.000 204.640 ;
    END
  END sstream_i[60]
  PIN sstream_i[61]
    DIRECTION INPUT ;
    USE SIGNAL ;
    ANTENNAGATEAREA 0.126000 ;
    PORT
      LAYER met3 ;
        RECT 0.000 206.760 4.000 207.360 ;
    END
  END sstream_i[61]
  PIN sstream_i[62]
    DIRECTION INPUT ;
    USE SIGNAL ;
    ANTENNAGATEAREA 0.126000 ;
    PORT
      LAYER met3 ;
        RECT 0.000 209.480 4.000 210.080 ;
    END
  END sstream_i[62]
  PIN sstream_i[63]
    DIRECTION INPUT ;
    USE SIGNAL ;
    ANTENNAGATEAREA 0.213000 ;
    PORT
      LAYER met3 ;
        RECT 0.000 212.200 4.000 212.800 ;
    END
  END sstream_i[63]
  PIN sstream_i[64]
    DIRECTION INPUT ;
    USE SIGNAL ;
    ANTENNAGATEAREA 0.126000 ;
    PORT
      LAYER met3 ;
        RECT 0.000 214.920 4.000 215.520 ;
    END
  END sstream_i[64]
  PIN sstream_i[65]
    DIRECTION INPUT ;
    USE SIGNAL ;
    ANTENNAGATEAREA 0.126000 ;
    PORT
      LAYER met3 ;
        RECT 0.000 217.640 4.000 218.240 ;
    END
  END sstream_i[65]
  PIN sstream_i[66]
    DIRECTION INPUT ;
    USE SIGNAL ;
    ANTENNAGATEAREA 0.126000 ;
    PORT
      LAYER met3 ;
        RECT 0.000 220.360 4.000 220.960 ;
    END
  END sstream_i[66]
  PIN sstream_i[67]
    DIRECTION INPUT ;
    USE SIGNAL ;
    ANTENNAGATEAREA 0.126000 ;
    PORT
      LAYER met3 ;
        RECT 0.000 223.080 4.000 223.680 ;
    END
  END sstream_i[67]
  PIN sstream_i[68]
    DIRECTION INPUT ;
    USE SIGNAL ;
    ANTENNAGATEAREA 0.126000 ;
    PORT
      LAYER met3 ;
        RECT 0.000 225.800 4.000 226.400 ;
    END
  END sstream_i[68]
  PIN sstream_i[69]
    DIRECTION INPUT ;
    USE SIGNAL ;
    ANTENNAGATEAREA 0.126000 ;
    PORT
      LAYER met3 ;
        RECT 0.000 228.520 4.000 229.120 ;
    END
  END sstream_i[69]
  PIN sstream_i[6]
    DIRECTION INPUT ;
    USE SIGNAL ;
    ANTENNAGATEAREA 0.126000 ;
    PORT
      LAYER met3 ;
        RECT 0.000 57.160 4.000 57.760 ;
    END
  END sstream_i[6]
  PIN sstream_i[70]
    DIRECTION INPUT ;
    USE SIGNAL ;
    ANTENNAGATEAREA 0.126000 ;
    PORT
      LAYER met3 ;
        RECT 0.000 231.240 4.000 231.840 ;
    END
  END sstream_i[70]
  PIN sstream_i[71]
    DIRECTION INPUT ;
    USE SIGNAL ;
    ANTENNAGATEAREA 0.126000 ;
    PORT
      LAYER met3 ;
        RECT 0.000 233.960 4.000 234.560 ;
    END
  END sstream_i[71]
  PIN sstream_i[72]
    DIRECTION INPUT ;
    USE SIGNAL ;
    ANTENNAGATEAREA 0.126000 ;
    PORT
      LAYER met3 ;
        RECT 0.000 236.680 4.000 237.280 ;
    END
  END sstream_i[72]
  PIN sstream_i[73]
    DIRECTION INPUT ;
    USE SIGNAL ;
    ANTENNAGATEAREA 0.126000 ;
    PORT
      LAYER met3 ;
        RECT 0.000 239.400 4.000 240.000 ;
    END
  END sstream_i[73]
  PIN sstream_i[74]
    DIRECTION INPUT ;
    USE SIGNAL ;
    ANTENNAGATEAREA 0.126000 ;
    PORT
      LAYER met3 ;
        RECT 0.000 242.120 4.000 242.720 ;
    END
  END sstream_i[74]
  PIN sstream_i[75]
    DIRECTION INPUT ;
    USE SIGNAL ;
    ANTENNAGATEAREA 0.126000 ;
    PORT
      LAYER met3 ;
        RECT 0.000 244.840 4.000 245.440 ;
    END
  END sstream_i[75]
  PIN sstream_i[76]
    DIRECTION INPUT ;
    USE SIGNAL ;
    ANTENNAGATEAREA 0.126000 ;
    PORT
      LAYER met3 ;
        RECT 0.000 247.560 4.000 248.160 ;
    END
  END sstream_i[76]
  PIN sstream_i[77]
    DIRECTION INPUT ;
    USE SIGNAL ;
    ANTENNAGATEAREA 0.126000 ;
    PORT
      LAYER met3 ;
        RECT 0.000 250.280 4.000 250.880 ;
    END
  END sstream_i[77]
  PIN sstream_i[78]
    DIRECTION INPUT ;
    USE SIGNAL ;
    ANTENNAGATEAREA 0.126000 ;
    PORT
      LAYER met3 ;
        RECT 0.000 253.000 4.000 253.600 ;
    END
  END sstream_i[78]
  PIN sstream_i[79]
    DIRECTION INPUT ;
    USE SIGNAL ;
    ANTENNAGATEAREA 0.126000 ;
    PORT
      LAYER met3 ;
        RECT 0.000 255.720 4.000 256.320 ;
    END
  END sstream_i[79]
  PIN sstream_i[7]
    DIRECTION INPUT ;
    USE SIGNAL ;
    ANTENNAGATEAREA 0.126000 ;
    PORT
      LAYER met3 ;
        RECT 0.000 59.880 4.000 60.480 ;
    END
  END sstream_i[7]
  PIN sstream_i[80]
    DIRECTION INPUT ;
    USE SIGNAL ;
    ANTENNAGATEAREA 0.126000 ;
    PORT
      LAYER met3 ;
        RECT 0.000 258.440 4.000 259.040 ;
    END
  END sstream_i[80]
  PIN sstream_i[81]
    DIRECTION INPUT ;
    USE SIGNAL ;
    ANTENNAGATEAREA 0.126000 ;
    PORT
      LAYER met3 ;
        RECT 0.000 261.160 4.000 261.760 ;
    END
  END sstream_i[81]
  PIN sstream_i[82]
    DIRECTION INPUT ;
    USE SIGNAL ;
    ANTENNAGATEAREA 0.126000 ;
    PORT
      LAYER met3 ;
        RECT 0.000 263.880 4.000 264.480 ;
    END
  END sstream_i[82]
  PIN sstream_i[83]
    DIRECTION INPUT ;
    USE SIGNAL ;
    ANTENNAGATEAREA 0.126000 ;
    PORT
      LAYER met3 ;
        RECT 0.000 266.600 4.000 267.200 ;
    END
  END sstream_i[83]
  PIN sstream_i[84]
    DIRECTION INPUT ;
    USE SIGNAL ;
    ANTENNAGATEAREA 0.126000 ;
    PORT
      LAYER met3 ;
        RECT 0.000 269.320 4.000 269.920 ;
    END
  END sstream_i[84]
  PIN sstream_i[85]
    DIRECTION INPUT ;
    USE SIGNAL ;
    ANTENNAGATEAREA 0.126000 ;
    PORT
      LAYER met3 ;
        RECT 0.000 272.040 4.000 272.640 ;
    END
  END sstream_i[85]
  PIN sstream_i[86]
    DIRECTION INPUT ;
    USE SIGNAL ;
    ANTENNAGATEAREA 0.126000 ;
    PORT
      LAYER met3 ;
        RECT 0.000 274.760 4.000 275.360 ;
    END
  END sstream_i[86]
  PIN sstream_i[87]
    DIRECTION INPUT ;
    USE SIGNAL ;
    ANTENNAGATEAREA 0.126000 ;
    PORT
      LAYER met3 ;
        RECT 0.000 277.480 4.000 278.080 ;
    END
  END sstream_i[87]
  PIN sstream_i[88]
    DIRECTION INPUT ;
    USE SIGNAL ;
    ANTENNAGATEAREA 0.126000 ;
    PORT
      LAYER met3 ;
        RECT 0.000 280.200 4.000 280.800 ;
    END
  END sstream_i[88]
  PIN sstream_i[89]
    DIRECTION INPUT ;
    USE SIGNAL ;
    ANTENNAGATEAREA 0.126000 ;
    PORT
      LAYER met3 ;
        RECT 0.000 282.920 4.000 283.520 ;
    END
  END sstream_i[89]
  PIN sstream_i[8]
    DIRECTION INPUT ;
    USE SIGNAL ;
    ANTENNAGATEAREA 0.126000 ;
    PORT
      LAYER met3 ;
        RECT 0.000 62.600 4.000 63.200 ;
    END
  END sstream_i[8]
  PIN sstream_i[90]
    DIRECTION INPUT ;
    USE SIGNAL ;
    ANTENNAGATEAREA 0.126000 ;
    PORT
      LAYER met3 ;
        RECT 0.000 285.640 4.000 286.240 ;
    END
  END sstream_i[90]
  PIN sstream_i[91]
    DIRECTION INPUT ;
    USE SIGNAL ;
    ANTENNAGATEAREA 0.126000 ;
    PORT
      LAYER met3 ;
        RECT 0.000 288.360 4.000 288.960 ;
    END
  END sstream_i[91]
  PIN sstream_i[92]
    DIRECTION INPUT ;
    USE SIGNAL ;
    ANTENNAGATEAREA 0.126000 ;
    PORT
      LAYER met3 ;
        RECT 0.000 291.080 4.000 291.680 ;
    END
  END sstream_i[92]
  PIN sstream_i[93]
    DIRECTION INPUT ;
    USE SIGNAL ;
    ANTENNAGATEAREA 0.126000 ;
    PORT
      LAYER met3 ;
        RECT 0.000 293.800 4.000 294.400 ;
    END
  END sstream_i[93]
  PIN sstream_i[94]
    DIRECTION INPUT ;
    USE SIGNAL ;
    ANTENNAGATEAREA 0.126000 ;
    PORT
      LAYER met3 ;
        RECT 0.000 296.520 4.000 297.120 ;
    END
  END sstream_i[94]
  PIN sstream_i[95]
    DIRECTION INPUT ;
    USE SIGNAL ;
    ANTENNAGATEAREA 0.213000 ;
    PORT
      LAYER met3 ;
        RECT 0.000 299.240 4.000 299.840 ;
    END
  END sstream_i[95]
  PIN sstream_i[96]
    DIRECTION INPUT ;
    USE SIGNAL ;
    ANTENNAGATEAREA 0.126000 ;
    PORT
      LAYER met3 ;
        RECT 0.000 301.960 4.000 302.560 ;
    END
  END sstream_i[96]
  PIN sstream_i[97]
    DIRECTION INPUT ;
    USE SIGNAL ;
    ANTENNAGATEAREA 0.126000 ;
    PORT
      LAYER met3 ;
        RECT 0.000 304.680 4.000 305.280 ;
    END
  END sstream_i[97]
  PIN sstream_i[98]
    DIRECTION INPUT ;
    USE SIGNAL ;
    ANTENNAGATEAREA 0.126000 ;
    PORT
      LAYER met3 ;
        RECT 0.000 307.400 4.000 308.000 ;
    END
  END sstream_i[98]
  PIN sstream_i[99]
    DIRECTION INPUT ;
    USE SIGNAL ;
    ANTENNAGATEAREA 0.126000 ;
    PORT
      LAYER met3 ;
        RECT 0.000 310.120 4.000 310.720 ;
    END
  END sstream_i[99]
  PIN sstream_i[9]
    DIRECTION INPUT ;
    USE SIGNAL ;
    ANTENNAGATEAREA 0.126000 ;
    PORT
      LAYER met3 ;
        RECT 0.000 65.320 4.000 65.920 ;
    END
  END sstream_i[9]
  PIN sstream_o
    DIRECTION OUTPUT TRISTATE ;
    USE SIGNAL ;
    ANTENNADIFFAREA 2.673000 ;
    PORT
      LAYER met3 ;
        RECT 0.000 356.360 4.000 356.960 ;
    END
  END sstream_o
  PIN vccd1
    DIRECTION INOUT ;
    USE POWER ;
    PORT
      LAYER met4 ;
        RECT 9.550 10.640 11.150 389.200 ;
    END
    PORT
      LAYER met4 ;
        RECT 19.210 10.640 20.810 389.200 ;
    END
    PORT
      LAYER met4 ;
        RECT 28.870 10.640 30.470 389.200 ;
    END
    PORT
      LAYER met4 ;
        RECT 38.530 10.640 40.130 389.200 ;
    END
  END vccd1
  PIN vssd1
    DIRECTION INOUT ;
    USE GROUND ;
    PORT
      LAYER met4 ;
        RECT 14.380 10.640 15.980 389.200 ;
    END
    PORT
      LAYER met4 ;
        RECT 24.040 10.640 25.640 389.200 ;
    END
    PORT
      LAYER met4 ;
        RECT 33.700 10.640 35.300 389.200 ;
    END
    PORT
      LAYER met4 ;
        RECT 43.360 10.640 44.960 389.200 ;
    END
  END vssd1
  OBS
      LAYER li1 ;
        RECT 5.520 10.795 44.160 389.045 ;
      LAYER met1 ;
        RECT 5.520 10.640 44.960 389.200 ;
      LAYER met2 ;
        RECT 5.610 4.280 44.930 389.145 ;
        RECT 5.610 3.670 8.090 4.280 ;
        RECT 8.930 3.670 24.650 4.280 ;
        RECT 25.490 3.670 41.210 4.280 ;
        RECT 42.050 3.670 44.930 4.280 ;
      LAYER met3 ;
        RECT 4.000 357.360 46.000 389.125 ;
        RECT 4.400 355.960 45.600 357.360 ;
        RECT 4.000 354.640 46.000 355.960 ;
        RECT 4.400 353.240 45.600 354.640 ;
        RECT 4.000 351.920 46.000 353.240 ;
        RECT 4.400 350.520 45.600 351.920 ;
        RECT 4.000 349.200 46.000 350.520 ;
        RECT 4.400 347.800 45.600 349.200 ;
        RECT 4.000 346.480 46.000 347.800 ;
        RECT 4.400 345.080 45.600 346.480 ;
        RECT 4.000 343.760 46.000 345.080 ;
        RECT 4.400 342.360 45.600 343.760 ;
        RECT 4.000 341.040 46.000 342.360 ;
        RECT 4.400 339.640 45.600 341.040 ;
        RECT 4.000 338.320 46.000 339.640 ;
        RECT 4.400 336.920 45.600 338.320 ;
        RECT 4.000 335.600 46.000 336.920 ;
        RECT 4.400 334.200 45.600 335.600 ;
        RECT 4.000 332.880 46.000 334.200 ;
        RECT 4.400 331.480 45.600 332.880 ;
        RECT 4.000 330.160 46.000 331.480 ;
        RECT 4.400 328.760 45.600 330.160 ;
        RECT 4.000 327.440 46.000 328.760 ;
        RECT 4.400 326.040 45.600 327.440 ;
        RECT 4.000 324.720 46.000 326.040 ;
        RECT 4.400 323.320 45.600 324.720 ;
        RECT 4.000 322.000 46.000 323.320 ;
        RECT 4.400 320.600 45.600 322.000 ;
        RECT 4.000 319.280 46.000 320.600 ;
        RECT 4.400 317.880 45.600 319.280 ;
        RECT 4.000 316.560 46.000 317.880 ;
        RECT 4.400 315.160 45.600 316.560 ;
        RECT 4.000 313.840 46.000 315.160 ;
        RECT 4.400 312.440 45.600 313.840 ;
        RECT 4.000 311.120 46.000 312.440 ;
        RECT 4.400 309.720 45.600 311.120 ;
        RECT 4.000 308.400 46.000 309.720 ;
        RECT 4.400 307.000 45.600 308.400 ;
        RECT 4.000 305.680 46.000 307.000 ;
        RECT 4.400 304.280 45.600 305.680 ;
        RECT 4.000 302.960 46.000 304.280 ;
        RECT 4.400 301.560 45.600 302.960 ;
        RECT 4.000 300.240 46.000 301.560 ;
        RECT 4.400 298.840 45.600 300.240 ;
        RECT 4.000 297.520 46.000 298.840 ;
        RECT 4.400 296.120 45.600 297.520 ;
        RECT 4.000 294.800 46.000 296.120 ;
        RECT 4.400 293.400 45.600 294.800 ;
        RECT 4.000 292.080 46.000 293.400 ;
        RECT 4.400 290.680 45.600 292.080 ;
        RECT 4.000 289.360 46.000 290.680 ;
        RECT 4.400 287.960 45.600 289.360 ;
        RECT 4.000 286.640 46.000 287.960 ;
        RECT 4.400 285.240 45.600 286.640 ;
        RECT 4.000 283.920 46.000 285.240 ;
        RECT 4.400 282.520 45.600 283.920 ;
        RECT 4.000 281.200 46.000 282.520 ;
        RECT 4.400 279.800 45.600 281.200 ;
        RECT 4.000 278.480 46.000 279.800 ;
        RECT 4.400 277.080 45.600 278.480 ;
        RECT 4.000 275.760 46.000 277.080 ;
        RECT 4.400 274.360 45.600 275.760 ;
        RECT 4.000 273.040 46.000 274.360 ;
        RECT 4.400 271.640 45.600 273.040 ;
        RECT 4.000 270.320 46.000 271.640 ;
        RECT 4.400 268.920 45.600 270.320 ;
        RECT 4.000 267.600 46.000 268.920 ;
        RECT 4.400 266.200 45.600 267.600 ;
        RECT 4.000 264.880 46.000 266.200 ;
        RECT 4.400 263.480 45.600 264.880 ;
        RECT 4.000 262.160 46.000 263.480 ;
        RECT 4.400 260.760 45.600 262.160 ;
        RECT 4.000 259.440 46.000 260.760 ;
        RECT 4.400 258.040 45.600 259.440 ;
        RECT 4.000 256.720 46.000 258.040 ;
        RECT 4.400 255.320 45.600 256.720 ;
        RECT 4.000 254.000 46.000 255.320 ;
        RECT 4.400 252.600 45.600 254.000 ;
        RECT 4.000 251.280 46.000 252.600 ;
        RECT 4.400 249.880 45.600 251.280 ;
        RECT 4.000 248.560 46.000 249.880 ;
        RECT 4.400 247.160 45.600 248.560 ;
        RECT 4.000 245.840 46.000 247.160 ;
        RECT 4.400 244.440 45.600 245.840 ;
        RECT 4.000 243.120 46.000 244.440 ;
        RECT 4.400 241.720 45.600 243.120 ;
        RECT 4.000 240.400 46.000 241.720 ;
        RECT 4.400 239.000 45.600 240.400 ;
        RECT 4.000 237.680 46.000 239.000 ;
        RECT 4.400 236.280 45.600 237.680 ;
        RECT 4.000 234.960 46.000 236.280 ;
        RECT 4.400 233.560 45.600 234.960 ;
        RECT 4.000 232.240 46.000 233.560 ;
        RECT 4.400 230.840 45.600 232.240 ;
        RECT 4.000 229.520 46.000 230.840 ;
        RECT 4.400 228.120 45.600 229.520 ;
        RECT 4.000 226.800 46.000 228.120 ;
        RECT 4.400 225.400 45.600 226.800 ;
        RECT 4.000 224.080 46.000 225.400 ;
        RECT 4.400 222.680 45.600 224.080 ;
        RECT 4.000 221.360 46.000 222.680 ;
        RECT 4.400 219.960 45.600 221.360 ;
        RECT 4.000 218.640 46.000 219.960 ;
        RECT 4.400 217.240 45.600 218.640 ;
        RECT 4.000 215.920 46.000 217.240 ;
        RECT 4.400 214.520 45.600 215.920 ;
        RECT 4.000 213.200 46.000 214.520 ;
        RECT 4.400 211.800 45.600 213.200 ;
        RECT 4.000 210.480 46.000 211.800 ;
        RECT 4.400 209.080 45.600 210.480 ;
        RECT 4.000 207.760 46.000 209.080 ;
        RECT 4.400 206.360 45.600 207.760 ;
        RECT 4.000 205.040 46.000 206.360 ;
        RECT 4.400 203.640 45.600 205.040 ;
        RECT 4.000 202.320 46.000 203.640 ;
        RECT 4.400 200.920 45.600 202.320 ;
        RECT 4.000 199.600 46.000 200.920 ;
        RECT 4.400 198.200 45.600 199.600 ;
        RECT 4.000 196.880 46.000 198.200 ;
        RECT 4.400 195.480 45.600 196.880 ;
        RECT 4.000 194.160 46.000 195.480 ;
        RECT 4.400 192.760 45.600 194.160 ;
        RECT 4.000 191.440 46.000 192.760 ;
        RECT 4.400 190.040 45.600 191.440 ;
        RECT 4.000 188.720 46.000 190.040 ;
        RECT 4.400 187.320 45.600 188.720 ;
        RECT 4.000 186.000 46.000 187.320 ;
        RECT 4.400 184.600 45.600 186.000 ;
        RECT 4.000 183.280 46.000 184.600 ;
        RECT 4.400 181.880 45.600 183.280 ;
        RECT 4.000 180.560 46.000 181.880 ;
        RECT 4.400 179.160 45.600 180.560 ;
        RECT 4.000 177.840 46.000 179.160 ;
        RECT 4.400 176.440 45.600 177.840 ;
        RECT 4.000 175.120 46.000 176.440 ;
        RECT 4.400 173.720 45.600 175.120 ;
        RECT 4.000 172.400 46.000 173.720 ;
        RECT 4.400 171.000 45.600 172.400 ;
        RECT 4.000 169.680 46.000 171.000 ;
        RECT 4.400 168.280 45.600 169.680 ;
        RECT 4.000 166.960 46.000 168.280 ;
        RECT 4.400 165.560 45.600 166.960 ;
        RECT 4.000 164.240 46.000 165.560 ;
        RECT 4.400 162.840 45.600 164.240 ;
        RECT 4.000 161.520 46.000 162.840 ;
        RECT 4.400 160.120 45.600 161.520 ;
        RECT 4.000 158.800 46.000 160.120 ;
        RECT 4.400 157.400 45.600 158.800 ;
        RECT 4.000 156.080 46.000 157.400 ;
        RECT 4.400 154.680 45.600 156.080 ;
        RECT 4.000 153.360 46.000 154.680 ;
        RECT 4.400 151.960 45.600 153.360 ;
        RECT 4.000 150.640 46.000 151.960 ;
        RECT 4.400 149.240 45.600 150.640 ;
        RECT 4.000 147.920 46.000 149.240 ;
        RECT 4.400 146.520 45.600 147.920 ;
        RECT 4.000 145.200 46.000 146.520 ;
        RECT 4.400 143.800 45.600 145.200 ;
        RECT 4.000 142.480 46.000 143.800 ;
        RECT 4.400 141.080 45.600 142.480 ;
        RECT 4.000 139.760 46.000 141.080 ;
        RECT 4.400 138.360 45.600 139.760 ;
        RECT 4.000 137.040 46.000 138.360 ;
        RECT 4.400 135.640 45.600 137.040 ;
        RECT 4.000 134.320 46.000 135.640 ;
        RECT 4.400 132.920 45.600 134.320 ;
        RECT 4.000 131.600 46.000 132.920 ;
        RECT 4.400 130.200 45.600 131.600 ;
        RECT 4.000 128.880 46.000 130.200 ;
        RECT 4.400 127.480 45.600 128.880 ;
        RECT 4.000 126.160 46.000 127.480 ;
        RECT 4.400 124.760 45.600 126.160 ;
        RECT 4.000 123.440 46.000 124.760 ;
        RECT 4.400 122.040 45.600 123.440 ;
        RECT 4.000 120.720 46.000 122.040 ;
        RECT 4.400 119.320 45.600 120.720 ;
        RECT 4.000 118.000 46.000 119.320 ;
        RECT 4.400 116.600 45.600 118.000 ;
        RECT 4.000 115.280 46.000 116.600 ;
        RECT 4.400 113.880 45.600 115.280 ;
        RECT 4.000 112.560 46.000 113.880 ;
        RECT 4.400 111.160 45.600 112.560 ;
        RECT 4.000 109.840 46.000 111.160 ;
        RECT 4.400 108.440 45.600 109.840 ;
        RECT 4.000 107.120 46.000 108.440 ;
        RECT 4.400 105.720 45.600 107.120 ;
        RECT 4.000 104.400 46.000 105.720 ;
        RECT 4.400 103.000 45.600 104.400 ;
        RECT 4.000 101.680 46.000 103.000 ;
        RECT 4.400 100.280 45.600 101.680 ;
        RECT 4.000 98.960 46.000 100.280 ;
        RECT 4.400 97.560 45.600 98.960 ;
        RECT 4.000 96.240 46.000 97.560 ;
        RECT 4.400 94.840 45.600 96.240 ;
        RECT 4.000 93.520 46.000 94.840 ;
        RECT 4.400 92.120 45.600 93.520 ;
        RECT 4.000 90.800 46.000 92.120 ;
        RECT 4.400 89.400 45.600 90.800 ;
        RECT 4.000 88.080 46.000 89.400 ;
        RECT 4.400 86.680 45.600 88.080 ;
        RECT 4.000 85.360 46.000 86.680 ;
        RECT 4.400 83.960 45.600 85.360 ;
        RECT 4.000 82.640 46.000 83.960 ;
        RECT 4.400 81.240 45.600 82.640 ;
        RECT 4.000 79.920 46.000 81.240 ;
        RECT 4.400 78.520 45.600 79.920 ;
        RECT 4.000 77.200 46.000 78.520 ;
        RECT 4.400 75.800 45.600 77.200 ;
        RECT 4.000 74.480 46.000 75.800 ;
        RECT 4.400 73.080 45.600 74.480 ;
        RECT 4.000 71.760 46.000 73.080 ;
        RECT 4.400 70.360 45.600 71.760 ;
        RECT 4.000 69.040 46.000 70.360 ;
        RECT 4.400 67.640 45.600 69.040 ;
        RECT 4.000 66.320 46.000 67.640 ;
        RECT 4.400 64.920 45.600 66.320 ;
        RECT 4.000 63.600 46.000 64.920 ;
        RECT 4.400 62.200 45.600 63.600 ;
        RECT 4.000 60.880 46.000 62.200 ;
        RECT 4.400 59.480 45.600 60.880 ;
        RECT 4.000 58.160 46.000 59.480 ;
        RECT 4.400 56.760 45.600 58.160 ;
        RECT 4.000 55.440 46.000 56.760 ;
        RECT 4.400 54.040 45.600 55.440 ;
        RECT 4.000 52.720 46.000 54.040 ;
        RECT 4.400 51.320 45.600 52.720 ;
        RECT 4.000 50.000 46.000 51.320 ;
        RECT 4.400 48.600 45.600 50.000 ;
        RECT 4.000 47.280 46.000 48.600 ;
        RECT 4.400 45.880 45.600 47.280 ;
        RECT 4.000 44.560 46.000 45.880 ;
        RECT 4.400 43.160 45.600 44.560 ;
        RECT 4.000 41.840 46.000 43.160 ;
        RECT 4.400 40.440 45.600 41.840 ;
        RECT 4.000 10.715 46.000 40.440 ;
      LAYER met4 ;
        RECT 16.855 123.935 18.105 259.585 ;
  END
END bary_check_pipe_m
END LIBRARY

